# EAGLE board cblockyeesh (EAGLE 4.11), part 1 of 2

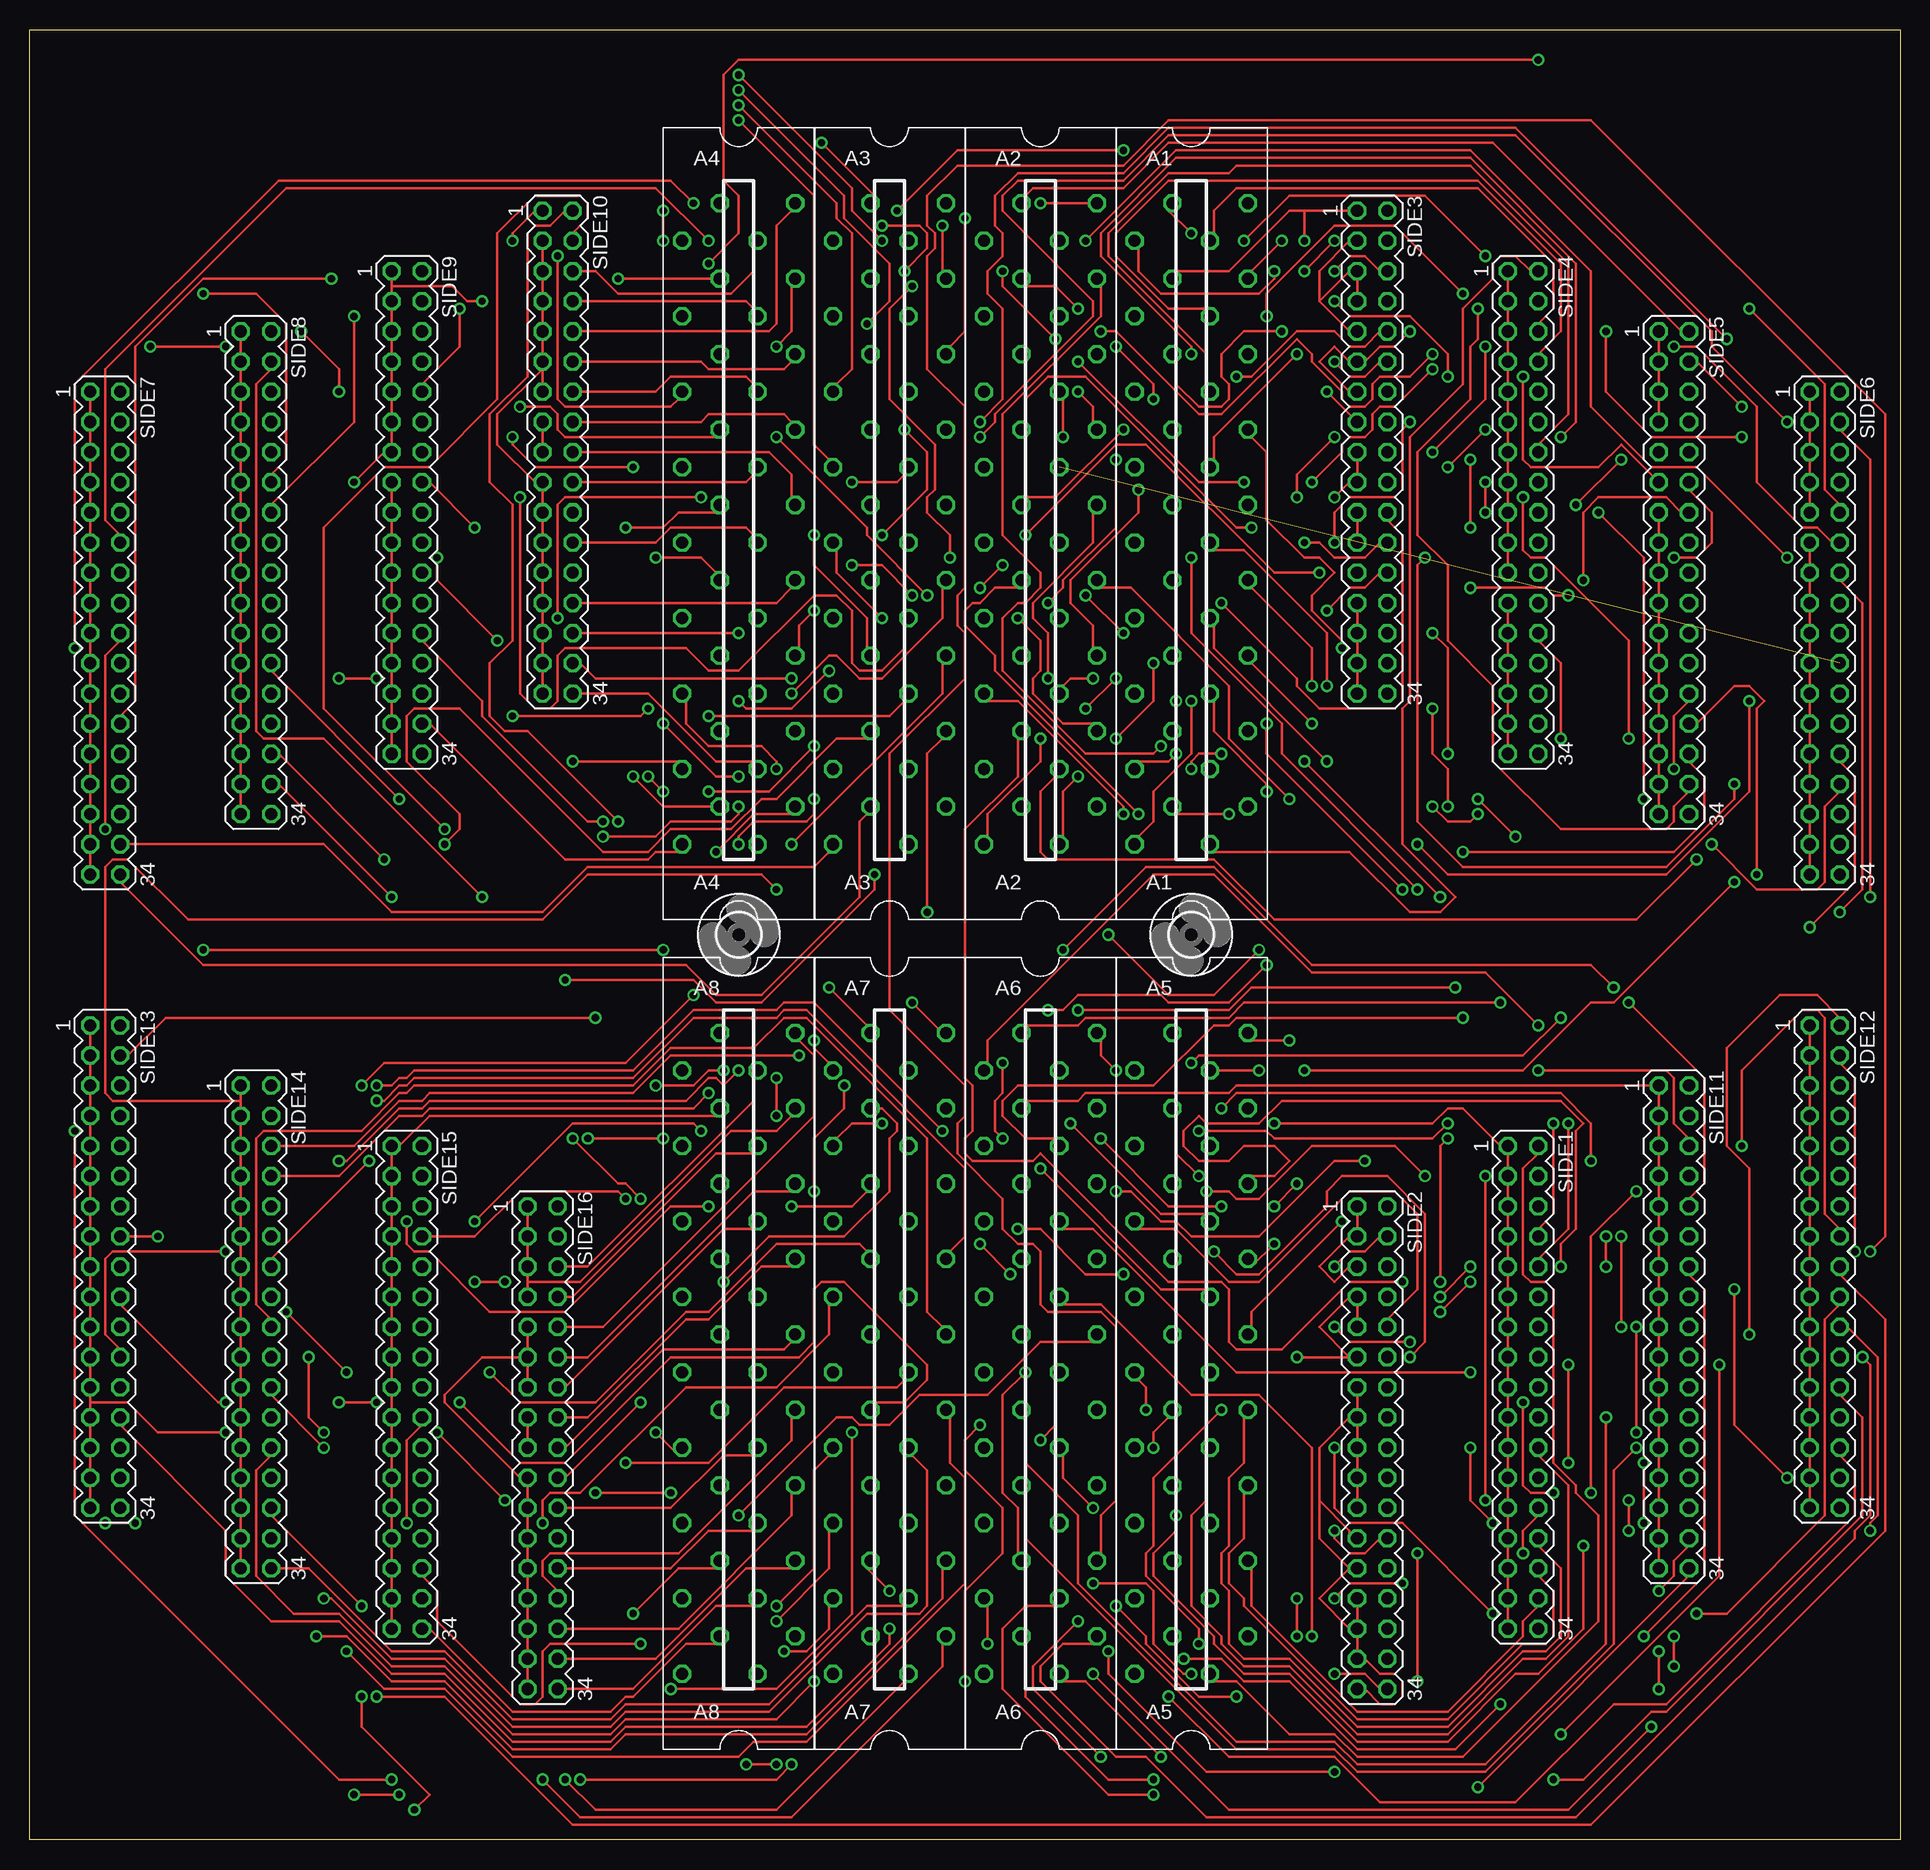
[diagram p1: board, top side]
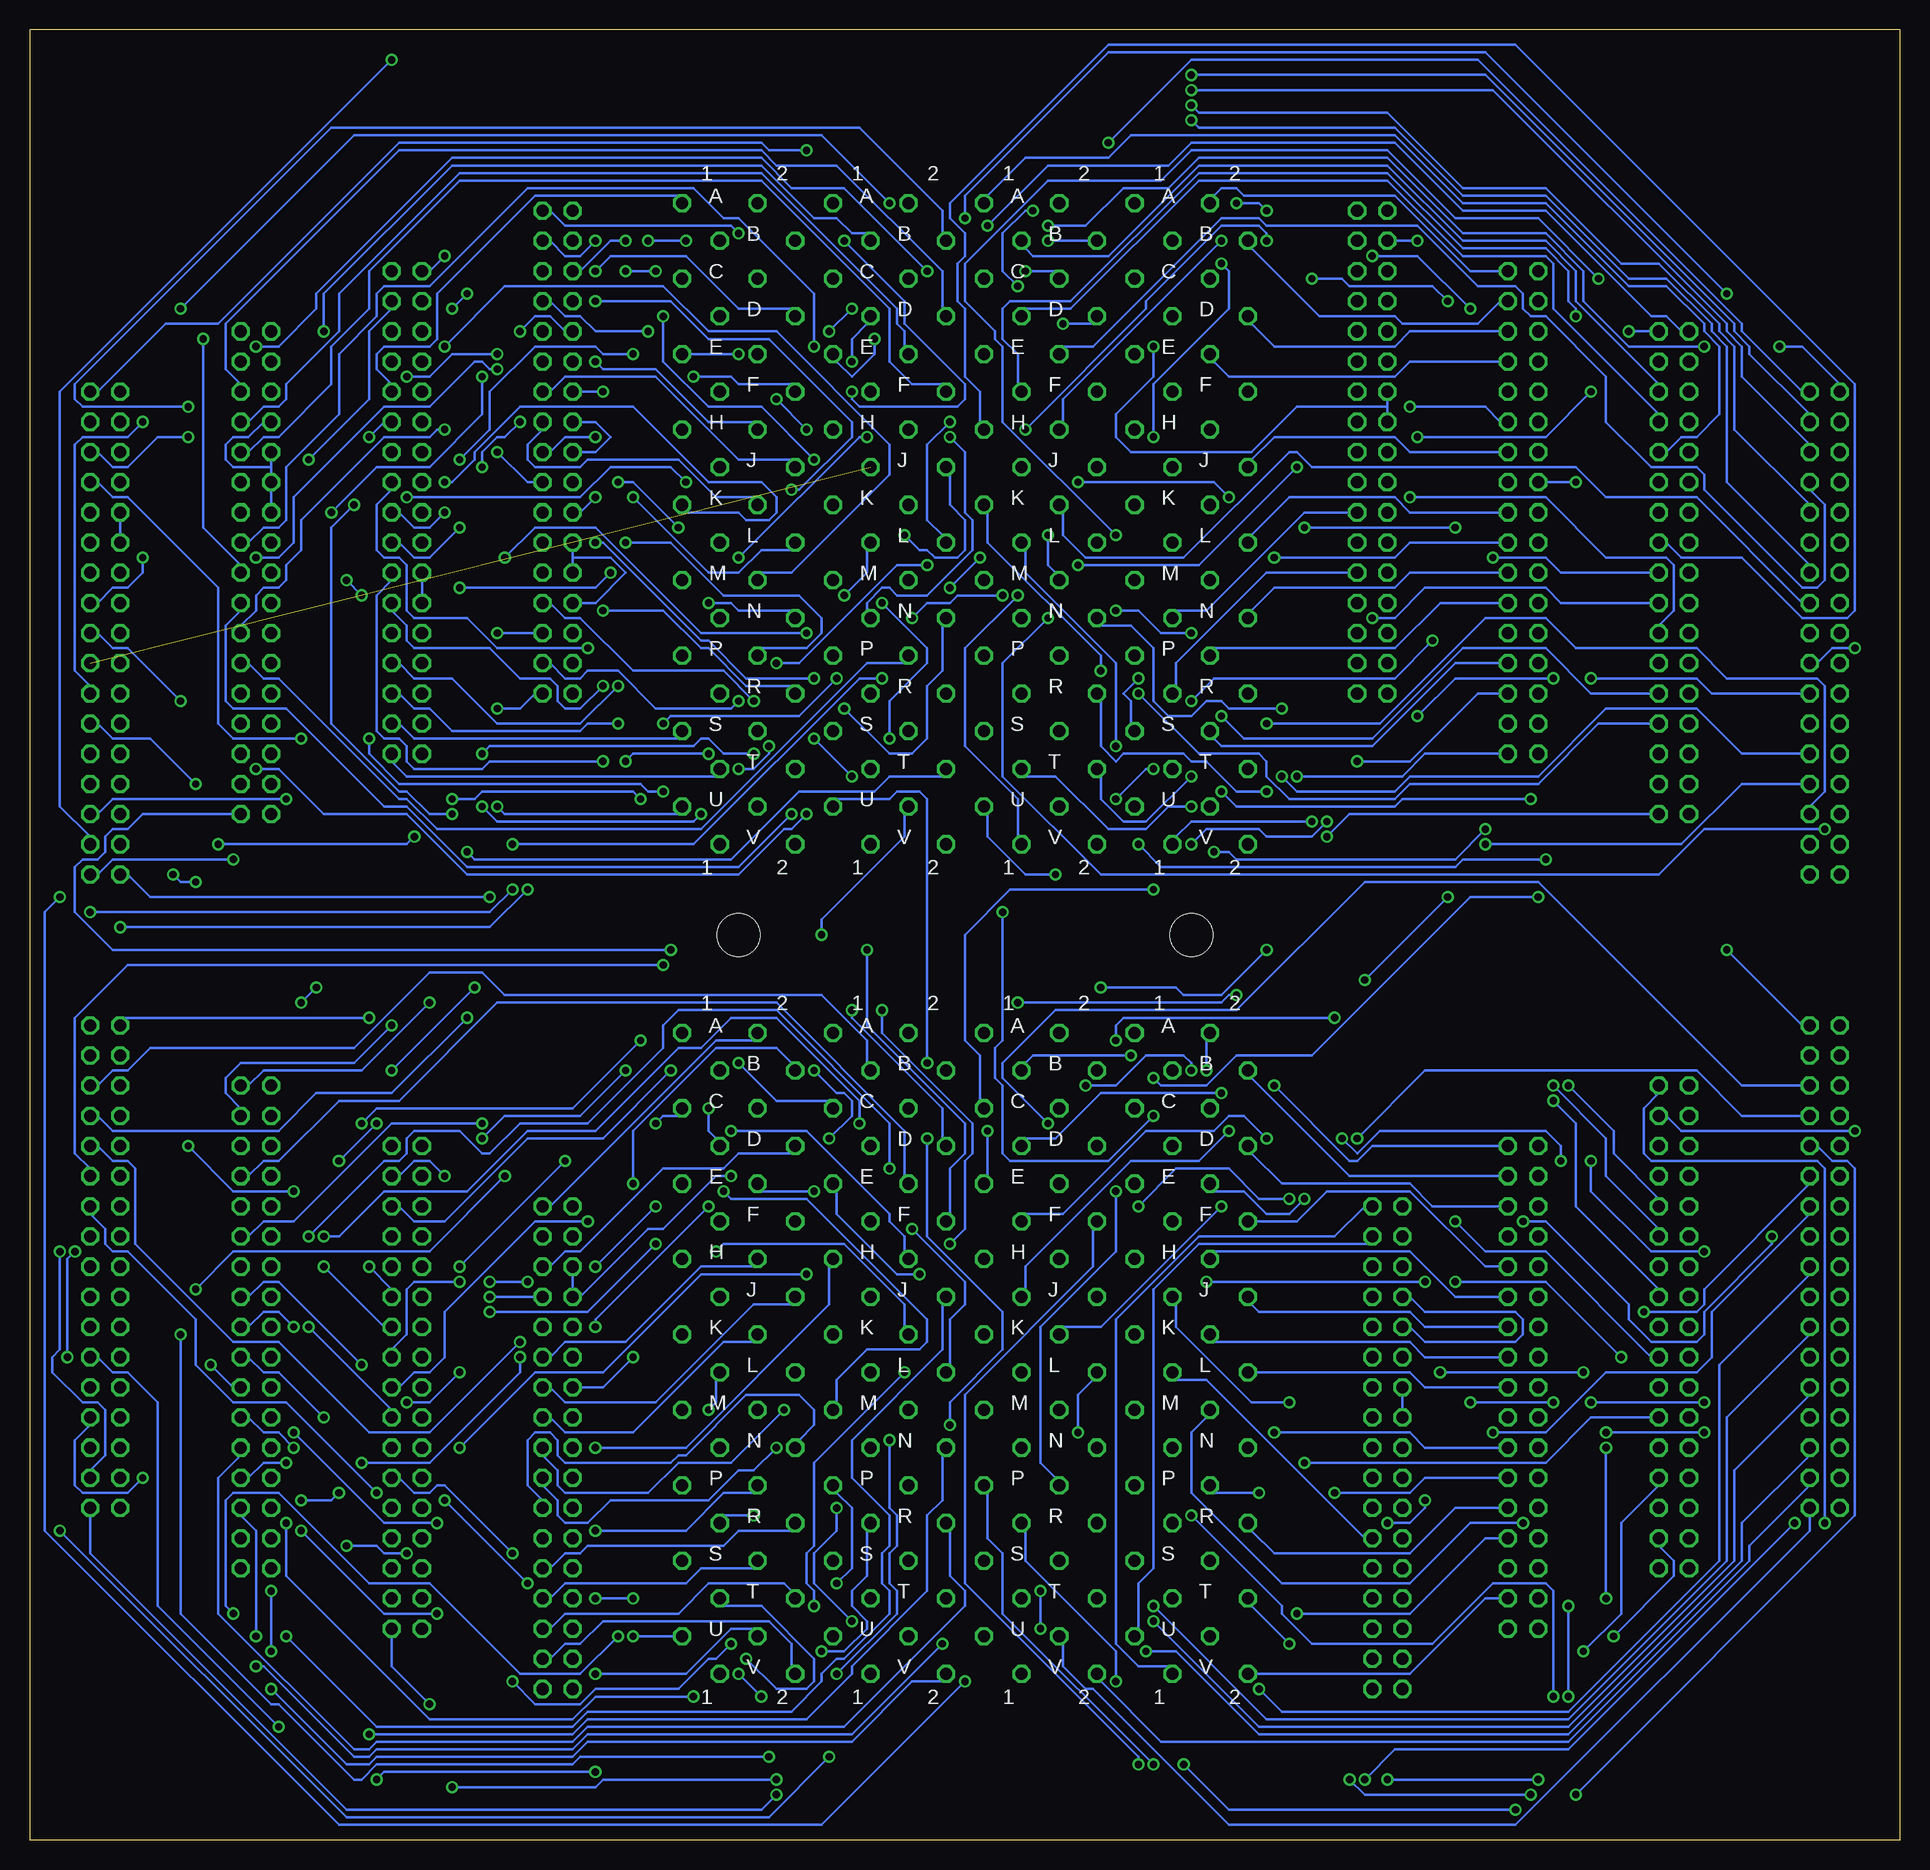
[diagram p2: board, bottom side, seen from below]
Size 157.48 x 152.4 mm. Coordinates in mm from the lower left corner, seen from the top.
Outline: 157.48,0 0,0 0,152.4 157.48,152.4 157.48,0
Copper layers (1*16): Top 0.035mm / dielectric 1.5mm / Bottom 0.035mm
Design rules "olimex8mil": minimum track width 8mil, minimum drill 24mil, track to track 8mil, track to pad 8mil, pad to pad 8mil, via to via 8mil, smd to smd 8mil, copper to edge 40mil, drill to drill 10mil, minimum pad ring 10mil, minimum via ring 8mil, stop-mask expansion 0mil, vias tented up to drill 0mil, thermal gap 10mil
Net classes: 1 Power: width 0.305 mm, drill 0.305 mm

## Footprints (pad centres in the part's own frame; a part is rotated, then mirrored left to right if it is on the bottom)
H807 = drill 1.016 octagon: A1 4.763,28.575; A2 -1.587,28.575; B1 1.587,25.4; B2 -4.763,25.4; C1 4.763,22.225; C2 -1.587,22.225; D1 1.587,19.05; D2 -4.763,19.05; E1 4.763,15.875; E2 -1.587,15.875; F1 1.587,12.7; F2 -4.763,12.7; H1 4.763,9.525; H2 -1.587,9.525; J1 1.587,6.35; J2 -4.763,6.35; K1 4.763,3.175; K2 -1.587,3.175; L1 1.587,0; L2 -4.763,0; M1 4.763,-3.175; M2 -1.587,-3.175; N1 1.587,-6.35; N2 -4.763,-6.35; P1 4.763,-9.525; P2 -1.587,-9.525; R1 1.587,-12.7; R2 -4.763,-12.7; S1 4.763,-15.875; S2 -1.587,-15.875; T1 1.587,-19.05; T2 -4.763,-19.05; U1 4.763,-22.225; U2 -1.587,-22.225; V1 1.587,-25.4; V2 -4.763,-25.4
MA17-2 = drill 1.016 octagon: 1 -20.32,-1.27; 2 -20.32,1.27; 3 -17.78,-1.27; 4 -17.78,1.27; 5 -15.24,-1.27; 6 -15.24,1.27; 7 -12.7,-1.27; 8 -12.7,1.27; 9 -10.16,-1.27; 10 -10.16,1.27; 11 -7.62,-1.27; 12 -7.62,1.27; 13 -5.08,-1.27; 14 -5.08,1.27; 15 -2.54,-1.27; 16 -2.54,1.27; 17 0,-1.27; 18 0,1.27; 19 2.54,-1.27; 20 2.54,1.27; 21 5.08,-1.27; 22 5.08,1.27; 23 7.62,-1.27; 24 7.62,1.27; 25 10.16,-1.27; 26 10.16,1.27; 27 12.7,-1.27; 28 12.7,1.27; 29 15.24,-1.27; 30 15.24,1.27; 31 17.78,-1.27; 32 17.78,1.27; 33 20.32,-1.27; 34 20.32,1.27
3,6 = hole 3.6: 0,0

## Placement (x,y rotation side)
A1  [H807]  97.79,109.22 0 top
A2  [H807]  85.09,109.22 0 top
A3  [H807]  72.39,109.22 0 top
A4  [H807]  59.69,109.22 0 top
A5  [H807]  97.79,39.37 0 top
A6  [H807]  85.09,39.37 0 top
A7  [H807]  72.39,39.37 0 top
A8  [H807]  59.69,39.37 0 top
SIDE1  [MA17-2]  125.73,38.1 270 top
SIDE2  [MA17-2]  113.03,33.02 270 top
SIDE3  [MA17-2]  113.03,116.84 270 top
SIDE4  [MA17-2]  125.73,111.76 270 top
SIDE5  [MA17-2]  138.43,106.68 270 top
SIDE6  [MA17-2]  151.13,101.6 270 top
SIDE7  [MA17-2]  6.35,101.6 270 top
SIDE8  [MA17-2]  19.05,106.68 270 top
SIDE9  [MA17-2]  31.75,111.76 270 top
SIDE10  [MA17-2]  44.45,116.84 270 top
SIDE11  [MA17-2]  138.43,43.18 270 top
SIDE12  [MA17-2]  151.13,48.26 270 top
SIDE13  [MA17-2]  6.35,48.26 270 top
SIDE14  [MA17-2]  19.05,43.18 270 top
SIDE15  [MA17-2]  31.75,38.1 270 top
SIDE16  [MA17-2]  43.18,33.02 270 top
U$5  [3,6]  59.69,76.2 0 top
U$6  [3,6]  97.79,76.2 0 top

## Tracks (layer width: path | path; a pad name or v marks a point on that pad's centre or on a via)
N$1  (via drill 0.61)
  Top 0.203: SIDE2.33 112.39,12.7 113.67,11.43 114.94,11.43 115.57,12.06 115.57,13.34 114.94,13.97 113.67,13.97 112.39,15.24 SIDE2.31 111.76,15.88 111.76,17.14 SIDE2.29 | SIDE2.27 111.76,19.68 111.76,18.41 SIDE2.29 | 111.12,22.86 108.58,20.32 111.12,17.78 SIDE2.29 | 111.12,22.86 SIDE2.25 111.12,22.86 | SIDE2.21 111.76,28.57 111.76,29.84 SIDE2.19 111.76,31.11 111.76,32.38 SIDE2.17 111.76,33.66 111.76,34.92 SIDE2.15 | 108.58,28.57 111.12,26.04 111.12,25.4 SIDE2.23 | 108.58,28.57 108.58,33.02 111.12,35.56 SIDE2.15 | SIDE2.13 111.76,37.47 111.76,36.2 SIDE2.15 | 111.12,22.86 108.58,25.4 108.58,28.57 | SIDE2.1 111.76,52.7 111.76,51.44 SIDE2.3 111.12,50.8 108.58,48.26 109.86,46.99 111.12,48.26 SIDE2.5 | v98.42,55.88 96.52,57.78 96.52,60.96 A5.C2 | 111.12,40.64 108.58,43.18 111.12,45.72 SIDE2.7 111.76,45.09 111.76,43.81 SIDE2.9 | 111.12,40.64 SIDE2.11 111.12,40.64 | v106.68,40.64 111.12,40.64
  Bottom 0.203: v98.42,55.88 99.69,55.88 104.14,51.44 105.41,51.44 111.12,45.72 SIDE2.7 111.76,46.35 111.76,47.62 SIDE2.5 | v106.68,40.64 109.22,38.1 111.12,38.1 SIDE2.13
N$2
  Bottom 0.203: A5.A2 96.52,67.31 99.69,67.31 113.67,53.34 SIDE2.2
N$3  (via drill 0.61)
  Top 0.203: v109.86,48.26 111.12,49.53 112.39,49.53 113.67,50.8 SIDE2.4 | v106.68,55.24 v104.78,53.34
  Bottom 0.203: v104.78,53.34 v109.86,48.26 | v106.68,55.24 106.68,59.69 99.69,66.67 94.61,66.67 93.34,65.41 A5.B2
N$4
  Bottom 0.203: A5.D2 93.34,57.78 97.79,57.78 99.06,56.52 104.14,56.52 111.12,49.53 112.39,49.53 113.67,48.26 SIDE2.6
N$5  (via drill 0.61)
  Top 0.203: v121.28,48.26 v118.75,45.72 | v112.39,57.15 109.86,57.15 103.5,50.8 97.79,50.8 96.52,52.07 95.25,52.07 92.71,54.61 v91.44,54.61
  Bottom 0.203: v118.75,45.72 114.94,45.72 SIDE2.8 | v112.39,57.15 v121.28,48.26 | v91.44,54.61 95.89,54.61 A5.E2
N$6
  Top 0.203: SIDE2.10 114.3,43.81 116.84,46.35 116.84,52.7 114.94,54.61 111.12,54.61 103.5,46.99 100.97,46.99 96.52,51.44 93.34,51.44 A5.F2
N$7
  Bottom 0.203: A5.H2 96.52,48.26 100.97,48.26 107.31,41.91 112.39,41.91 113.67,40.64 SIDE2.12
N$8
  Bottom 0.203: SIDE2.14 113.67,38.1 112.39,36.83 104.78,36.83 96.52,45.09 93.34,45.09 A5.J2
N$9
  Bottom 0.203: SIDE2.16 113.67,35.56 112.39,34.29 106.68,34.29 99.06,41.91 96.52,41.91 A5.K2
N$10  (via drill 0.61)
  Top 0.203: v93.98,36.2 93.98,38.1 93.34,38.73 A5.L2
  Bottom 0.203: v93.98,36.2 98.42,31.75 102.87,31.75 105.41,29.21 112.39,29.21 113.03,29.84 113.03,31.11 114.3,32.38 SIDE2.18
N$11  (via drill 0.61)
  Top 0.203: v94.61,33.02 94.61,34.29 95.89,35.56 A5.M2
  Bottom 0.203: v94.61,33.02 96.52,31.11 97.79,31.11 100.33,28.57 108.58,28.57 110.49,26.67 112.39,26.67 113.03,27.3 113.03,28.57 114.3,29.84 SIDE2.20
N$12
  Bottom 0.203: SIDE2.22 114.3,28.57 115.57,29.84 115.57,33.66 114.94,34.29 113.67,34.29 113.03,33.66 113.03,32.38 112.39,31.75 103.5,31.75 102.87,32.38 102.23,32.38 97.16,37.47 92.71,37.47 91.44,36.2 91.44,34.92 92.71,33.66 A5.N2
N$13  (via drill 0.61)
  Top 0.203: v109.86,26.04 109.86,25.4 111.12,24.13 112.39,24.13 113.67,25.4 SIDE2.24
  Bottom 0.203: v109.86,26.04 102.23,26.04 99.06,29.21 96.52,29.21 A5.P2
N$14
  Bottom 0.203: A5.R2 93.34,26.04 97.79,26.04 99.06,24.77 110.49,24.77 111.12,24.13 112.39,24.13 113.67,22.86 SIDE2.26
N$15
  Bottom 0.203: A5.S2 96.52,22.86 100.97,22.86 102.23,21.59 112.39,21.59 113.67,20.32 SIDE2.28
N$16
  Bottom 0.203: SIDE2.30 113.67,17.78 112.39,19.05 102.87,19.05 100.33,21.59 93.98,21.59 93.34,20.95 A5.T2
N$17  (via drill 0.61)
  Top 0.203: v109.86,13.97 112.39,13.97 113.67,12.7 SIDE2.34
  Bottom 0.203: v109.86,13.97 102.23,13.97 98.42,17.78 96.52,17.78 A5.U2
N$18
  Bottom 0.203: A5.V2 93.34,14.61 93.34,16.51 95.25,18.41 109.22,18.41 111.12,16.51 112.39,16.51 113.67,15.24 SIDE2.32
N$19  (via drill 0.61)
  Top 0.203: v129.54,60.33 129.54,51.44 127,48.9 SIDE1.10 | v106.05,67.31 102.87,67.31 A5.A1
  Bottom 0.203: v129.54,60.33 128.27,61.59 111.76,61.59 v106.05,67.31
N$20  (via drill 0.61)
  Top 0.203: v103.5,64.77 99.69,64.77 A5.B1
  Bottom 0.203: v103.5,64.77 109.22,59.05 115.57,59.05 122.56,52.07 125.09,52.07 126.36,53.34 SIDE1.6
N$21  (via drill 0.61)
  Top 0.203: v128.27,60.33 128.27,52.7 127,51.44 SIDE1.8 | v131.44,57.15 131.44,60.33 128.91,62.87 101.6,62.87 v100.33,61.59
  Bottom 0.203: v131.44,57.15 v128.27,60.33 | v100.33,61.59 100.33,59.69 99.69,59.05 A5.D1
N$22  (via drill 0.61)
  Top 0.203: v128.91,48.26 128.91,50.16 130.18,51.44 130.18,59.69 130.81,60.33 128.91,62.23 105.41,62.23 103.5,60.33 99.06,60.33 98.42,60.96 97.16,59.69 97.16,58.42 98.42,57.15 100.97,57.15 102.23,58.42 104.78,58.42 106.05,57.15 104.78,55.88 102.87,55.88 A5.E1
  Bottom 0.203: v128.91,48.26 127,46.35 SIDE1.12
N$23  (via drill 0.61)
  Top 0.203: v132.72,50.8 v132.72,48.26 | v87.63,60.33 95.25,52.7 99.06,52.7 A5.F1
  Bottom 0.203: v132.72,48.26 127.64,43.18 SIDE1.14 | v132.72,50.8 131.44,50.8 127.64,54.61 120.65,54.61 115.57,59.69 109.86,59.69 102.87,66.67 100.97,66.67 98.42,69.22 94.61,69.22 87.63,62.23 v87.63,60.33
N$24  (via drill 0.61)
  Top 0.203: v118.75,44.45 v121.28,46.99 | v104.78,50.16 102.87,48.26 A5.H1
  Bottom 0.203: v121.28,46.99 125.09,46.99 125.73,46.35 125.73,42.55 127,41.27 SIDE1.16 | v118.75,44.45 110.49,44.45 v104.78,50.16
N$25  (via drill 0.61)
  Top 0.203: v133.99,50.8 v133.99,43.18 | v85.09,56.52 95.25,46.35 99.06,46.35 A5.J1
  Bottom 0.203: v133.99,43.18 127,36.2 SIDE1.20 | v133.99,50.8 127.64,57.15 126.36,57.15 125.73,57.78 125.73,59.05 125.09,59.69 121.28,59.69 119.38,57.78 118.75,57.78 116.2,60.33 110.49,60.33 104.14,66.67 104.14,68.58 102.87,69.85 94.61,69.85 85.09,60.33 v85.09,56.52
N$26  (via drill 0.61)
  Top 0.203: v110.49,52.07 102.87,44.45 102.87,43.18 A5.K1
  Bottom 0.203: v110.49,52.07 114.94,52.07 122.56,44.45 122.56,40.64 123.83,39.37 125.09,39.37 126.36,38.1 SIDE1.18
N$27  (via drill 0.61)
  Top 0.203: v100.33,36.2 94.61,30.48 94.61,24.77 93.98,24.13 93.98,22.23 98.42,17.78 v98.42,16.51 | v116.84,13.34 v116.84,24.13
  Bottom 0.203: v100.33,36.2 99.69,36.83 99.69,38.73 A5.L1 | v98.42,16.51 99.69,15.24 100.33,15.24 102.87,12.7 109.86,12.7 111.12,11.43 114.94,11.43 v116.84,13.34 | v116.84,24.13 122.56,29.84 123.19,29.84 123.83,29.21 125.09,29.21 126.36,30.48 SIDE1.24
N$28
  Top 0.203: A5.M1 102.23,35.56 102.23,31.75 100.97,30.48 100.97,24.77 100.33,24.13 100.33,21.59 100.97,20.95 100.97,16.51 102.23,15.24 106.05,15.24 111.76,9.53 119.38,9.53 125.73,15.88 127.64,15.88 128.91,17.14 128.91,22.86 127,24.77 SIDE1.28
N$29
  Top 0.203: A5.N1 99.06,32.38 99.06,28.57 97.79,27.3 97.79,19.68 100.33,17.14 100.33,16.51 102.23,14.61 106.05,14.61 111.76,8.89 119.38,8.89 125.73,15.24 127.64,15.24 129.54,17.14 129.54,29.84 127,32.38 SIDE1.22
N$30
  Top 0.203: A5.P1 102.23,29.21 102.23,25.4 100.97,24.13 100.97,21.59 102.23,20.32 102.23,19.68 111.76,10.16 119.38,10.16 125.73,16.51 127.64,16.51 128.27,17.14 128.27,20.95 127,22.23 SIDE1.30
N$31  (via drill 0.61)
  Top 0.203: v96.52,27.3 96.52,26.04 94.61,24.13 94.61,22.23 99.69,17.14 99.69,16.51 102.23,13.97 106.05,13.97 111.76,8.26 119.38,8.26 125.09,13.97 127,13.97 130.81,17.78 v130.81,24.77 | v125.73,24.13 125.73,26.04 127,27.3 SIDE1.26
  Bottom 0.203: v96.52,27.3 99.06,27.3 A5.R1 | v130.81,24.77 128.27,24.77 127.64,24.13 v125.73,24.13
N$32
  Top 0.203: A5.S1 102.87,22.86 102.87,19.68 111.76,10.79 119.38,10.79 125.73,17.14 125.73,18.41 127,19.68 SIDE1.32
N$33  (via drill 0.61)
  Top 0.203: v123.83,11.43 120.02,7.62 111.76,7.62 106.05,13.34 102.23,13.34 100.33,15.24 v97.16,15.24
  Bottom 0.203: v123.83,11.43 127,14.61 127,17.14 SIDE1.34 | v97.16,15.24 94.61,12.7 92.08,12.7 91.44,13.34 91.44,15.24 95.89,19.68 99.06,19.68 A5.T1
N$34  (via drill 0.61)
  Top 0.203: v106.68,17.14 v106.68,20.32 | v109.86,20.32 111.12,21.59 v115.57,21.59 | v122.56,28.57 v122.56,55.88
  Bottom 0.203: v106.68,17.14 102.87,17.14 A5.U1 | v106.68,20.32 v109.86,20.32 | v115.57,21.59 v122.56,28.57 | v122.56,55.88 123.83,57.15 125.09,57.15 126.36,55.88 SIDE1.4
N$35
  Top 0.203: A5.V1 99.69,13.34 101.6,13.34 106.05,8.89 109.86,8.89 111.76,6.99 120.65,6.99 132.08,18.41 132.08,27.3 130.18,29.21 130.18,29.84 128.27,31.75 128.27,46.35 127.64,46.99 126.36,46.99 125.73,47.62 125.73,56.52 127,57.78 SIDE1.2
N$36  (via drill 0.61)
  Top 0.203: SIDE1.33 124.46,18.41 124.46,19.68 SIDE1.31 124.46,20.95 124.46,22.23 SIDE1.29 124.46,23.5 124.46,24.77 SIDE1.27 124.46,26.04 124.46,27.3 SIDE1.25 124.46,28.57 124.46,29.84 SIDE1.23 124.46,31.11 124.46,32.38 SIDE1.21 124.46,33.66 124.46,34.92 SIDE1.19 124.46,36.2 124.46,37.47 SIDE1.17 124.46,38.73 124.46,40.01 SIDE1.15 124.46,41.27 124.46,42.55 SIDE1.13 124.46,43.81 124.46,45.09 SIDE1.11 124.46,46.35 124.46,47.62 SIDE1.9 124.46,48.9 124.46,50.16 SIDE1.7 124.46,51.44 124.46,52.7 SIDE1.5 124.46,53.98 124.46,55.24 SIDE1.3 124.46,56.52 124.46,57.78 SIDE1.1 123.83,58.42 120.65,61.59 119.38,61.59 118.11,60.33 v104.78,60.33
  Bottom 0.203: v104.78,60.33 104.14,60.96 102.87,60.96 A5.C1
N$37  (via drill 0.61)
  Top 0.203: 108.58,129.54 111.12,127 SIDE3.9 | 108.58,129.54 111.12,132.08 SIDE3.5 111.76,131.44 111.76,130.18 SIDE3.7 | 108.58,129.54 108.58,132.08 111.12,134.62 SIDE3.3 | 107.31,137.16 111.12,137.16 SIDE3.1 | 107.31,137.16 106.05,137.16 100.97,132.08 96.52,132.08 A1.C2 | v107.31,134.62 107.31,137.16 | SIDE3.33 111.76,97.16 111.76,98.42 SIDE3.31 111.76,99.69 111.76,100.97 SIDE3.29 111.76,102.23 111.76,103.5 SIDE3.27 | SIDE3.21 111.76,111.12 111.76,109.86 SIDE3.23 | SIDE3.13 111.12,121.92 108.58,124.46 109.86,125.73 111.12,124.46 SIDE3.11 112.39,124.46 113.67,125.73 114.94,125.73 v116.2,127 | SIDE3.17 111.76,116.2 111.76,114.94 SIDE3.19 111.12,114.3 v109.86,113.03 | SIDE3.15 v109.22,121.92
  Bottom 0.203: v107.31,134.62 108.58,134.62 111.12,132.08 SIDE3.5 | 111.76,107.95 111.76,108.58 SIDE3.23 | 111.76,107.95 111.76,107.31 SIDE3.25 | SIDE3.15 111.12,119.38 109.86,119.38 108.58,118.11 109.86,116.84 111.12,116.84 SIDE3.17 | v109.22,121.92 111.12,121.92 SIDE3.13 | v109.86,113.03 111.12,111.76 SIDE3.21 | 111.76,107.95 108.58,107.95 107.31,106.68 109.86,104.14 111.12,104.14 SIDE3.27 | v116.2,127 114.94,128.27 113.67,128.27 112.39,127 SIDE3.9
N$38  (via drill 0.61)
  Top 0.203: v97.79,135.25 95.89,137.16 A1.A2
  Bottom 0.203: v97.79,135.25 98.42,135.89 112.39,135.89 113.67,137.16 SIDE3.2
N$39  (via drill 0.61)
  Top 0.203: v104.78,132.08 104.78,131.44 103.5,130.18 95.25,130.18 93.34,132.08 93.34,133.99 A1.B2 | v107.31,132.08 v109.86,134.62
  Bottom 0.203: v104.78,132.08 v107.31,132.08 | v109.86,134.62 111.12,133.35 112.39,133.35 113.67,134.62 SIDE3.4
N$40  (via drill 0.61)
  Top 0.203: v109.86,132.08 111.12,133.35 112.39,133.35 113.67,132.08 SIDE3.6
  Bottom 0.203: v109.86,132.08 108.58,133.35 102.23,133.35 97.79,128.91 93.34,128.91 A1.D2
N$41  (via drill 0.61)
  Top 0.203: v105.41,127 102.23,127 100.33,125.09 100.33,123.19 100.97,122.56 100.97,121.28 100.33,120.65 98.42,120.65 96.52,122.56 96.52,124.46 A1.E2
  Bottom 0.203: v105.41,127 109.86,127 111.12,128.27 112.39,128.27 113.67,129.54 SIDE3.8
N$42  (via drill 0.61)
  Top 0.203: v101.6,123.19 102.87,123.19 106.68,127 109.86,127 111.12,125.73 112.39,125.73 113.67,127 SIDE3.10
  Bottom 0.203: v101.6,123.19 98.42,123.19 97.79,122.56 93.34,122.56 A1.F2
N$43  (via drill 0.61)
  Top 0.203: v109.86,124.46 111.12,123.19 112.39,123.19 113.67,124.46 SIDE3.12
  Bottom 0.203: v109.86,124.46 109.22,123.83 104.78,123.83 100.33,119.38 96.52,119.38 A1.H2
N$44
  Bottom 0.203: A1.J2 93.34,116.2 97.79,116.2 104.78,123.19 112.39,123.19 113.67,121.92 SIDE3.14
N$45
  Bottom 0.203: A1.K2 96.52,113.03 99.69,113.03 102.87,116.2 110.49,116.2 111.12,115.57 114.94,115.57 115.57,116.2 115.57,117.47 114.3,118.75 SIDE3.16
N$46  (via drill 0.61)
  Top 0.203: v106.68,113.03 106.68,114.94 v109.86,118.11
  Bottom 0.203: v106.68,113.03 100.33,106.68 97.79,106.68 95.89,108.58 93.34,108.58 A1.L2 | v109.86,118.11 112.39,118.11 113.67,116.84 SIDE3.18
N$47  (via drill 0.61)
  Top 0.203: v122.56,125.73 122.56,121.28 v118.11,116.84
  Bottom 0.203: v122.56,125.73 117.47,130.81 104.14,130.81 100.33,127 94.61,127 85.09,117.47 85.09,114.94 93.34,106.68 95.89,106.68 A1.M2 | v118.11,116.84 115.57,114.3 114.94,114.3 SIDE3.20
N$48  (via drill 0.61)
  Top 0.203: v100.33,104.14 106.68,97.79 106.68,97.16 108.58,95.25 114.94,95.25 115.57,95.89 115.57,109.86 114.3,111.12 SIDE3.22
  Bottom 0.203: v100.33,104.14 98.42,104.14 97.79,103.5 93.34,103.5 A1.N2
N$49  (via drill 0.61)
  Top 0.203: v107.31,109.22 108.58,109.22 109.86,107.95 112.39,107.95 113.67,109.22 SIDE3.24
  Bottom 0.203: v107.31,109.22 103.5,109.22 99.06,104.78 92.71,104.78 90.81,102.87 90.81,101.6 92.08,100.33 95.89,100.33 A1.P2
N$50  (via drill 0.61)
  Top 0.203: v109.22,103.5 111.12,105.41 112.39,105.41 113.67,106.68 SIDE3.26
  Bottom 0.203: v109.22,103.5 104.14,103.5 100.97,100.33 100.33,100.33 97.16,97.16 93.34,97.16 A1.R2
N$51  (via drill 0.61)
  Top 0.203: v96.52,95.89 96.52,93.98 A1.S2
  Bottom 0.203: v96.52,95.89 99.06,98.42 106.68,98.42 111.12,102.87 112.39,102.87 113.67,104.14 SIDE3.28
N$52  (via drill 0.61)
  Top 0.203: v96.52,91.44 95.89,90.81 93.34,90.81 A1.T2 | v119.38,91.44 119.38,100.33 v118.11,101.6
  Bottom 0.203: v96.52,91.44 99.06,91.44 100.33,92.71 100.97,92.71 101.6,92.08 118.75,92.08 v119.38,91.44 | v118.11,101.6 114.94,101.6 SIDE3.30
N$53  (via drill 0.61)
  Top 0.203: v100.97,86.36 96.52,86.36 A1.U2 | v119.38,87 119.38,90.17 118.11,91.44 v118.11,95.25
  Bottom 0.203: v100.97,86.36 101.6,85.72 118.11,85.72 v119.38,87 | v118.11,95.25 116.2,95.25 114.94,96.52 SIDE3.34
N$54  (via drill 0.61)
  Top 0.203: v97.79,95.89 97.79,91.44 94.61,88.27 94.61,85.72 93.34,84.45 A1.V2
  Bottom 0.203: v97.79,95.89 98.42,95.25 104.78,95.25 107.95,98.42 110.49,98.42 111.12,97.79 112.39,97.79 113.67,99.06 SIDE3.32
N$55
  Bottom 0.203: A1.A1 102.87,138.43 114.94,138.43 123.19,130.18 123.19,126.36 123.83,125.73 127.64,125.73 128.27,125.09 128.27,123.83 127,122.56 SIDE4.10
N$56
  Top 0.203: A1.B1 99.69,135.25 99.69,137.16 101.6,139.06 121.92,139.06 128.27,132.72 128.27,128.91 127,127.64 SIDE4.6
N$57
  Top 0.203: SIDE4.8 127,125.09 128.91,127 128.91,132.72 121.92,139.7 95.89,139.7 91.44,135.25 91.44,133.35 95.89,128.91 99.06,128.91 A1.D1
N$58  (via drill 0.61)
  Top 0.203: v128.91,118.11 130.18,119.38 130.18,132.72 121.28,141.6 96.52,141.6 90.17,135.25 90.17,133.35 97.79,125.73 v97.79,125.09
  Bottom 0.203: v128.91,118.11 127.64,119.38 SIDE4.12 | v97.79,125.09 102.23,125.09 A1.E1
N$59
  Top 0.203: A1.F1 99.06,122.56 99.06,125.09 90.81,133.35 90.81,135.25 95.89,140.34 100.97,140.34 101.6,140.97 121.28,140.97 129.54,132.72 129.54,120.02 127,117.47 SIDE4.14
N$60  (via drill 0.61)
  Top 0.203: v110.49,100.33 110.49,100.97 107.95,103.5 107.95,104.78 109.86,106.68 108.58,107.95 107.31,107.95 104.14,111.12 104.14,116.84 102.87,118.11 A1.H1
  Bottom 0.203: v110.49,100.33 118.11,100.33 120.65,102.87 125.09,102.87 125.73,103.5 125.73,107.31 126.36,107.95 127.64,107.95 128.27,108.58 128.27,112.39 127,113.67 SIDE4.16
N$61  (via drill 0.61)
  Top 0.203: v106.68,125.09 99.69,118.11 99.69,116.2 A1.J1 | v121.28,116.2 v121.28,110.49
  Bottom 0.203: v106.68,125.09 109.22,125.09 109.86,125.73 114.94,125.73 118.75,121.92 118.75,118.75 v121.28,116.2 | v121.28,110.49 123.83,107.95 125.09,107.95 126.36,109.22 SIDE4.20
N$62  (via drill 0.61)
  Top 0.203: v122.56,114.3 v122.56,111.76
  Bottom 0.203: v122.56,114.3 121.92,114.3 120.02,116.2 120.02,116.84 116.2,120.65 106.68,120.65 100.33,114.3 95.89,114.3 94.61,113.03 94.61,111.76 95.25,111.12 97.16,111.12 97.79,111.76 102.23,111.76 A1.K1 | v122.56,111.76 123.83,110.49 125.09,110.49 126.36,111.76 SIDE4.18
N$63  (via drill 0.61)
  Top 0.203: v109.22,97.16 109.22,101.6 102.23,108.58 99.69,108.58 A1.L1
  Bottom 0.203: v109.22,97.16 111.12,95.25 112.39,95.25 113.03,95.89 113.03,97.16 113.67,97.79 116.2,97.79 118.75,100.33 125.09,100.33 125.73,100.97 125.73,102.23 127,103.5 SIDE4.24
N$64  (via drill 0.61)
  Top 0.203: v107.95,97.16 107.95,100.33 102.87,105.41 A1.M1
  Bottom 0.203: v107.95,97.16 111.12,93.98 118.11,93.98 121.92,97.79 125.09,97.79 126.36,99.06 SIDE4.28
N$65  (via drill 0.61)
  Top 0.203: v109.22,90.81 99.69,100.33 99.69,102.23 A1.N1
  Bottom 0.203: v109.22,90.81 118.75,90.81 119.38,90.17 125.09,90.17 125.73,90.81 125.73,92.08 126.36,92.71 127.64,92.71 128.27,93.34 128.27,104.78 127,106.05 SIDE4.22
N$66  (via drill 0.61)
  Top 0.203: v107.95,93.98 102.87,99.06 A1.P1
  Bottom 0.203: v107.95,93.98 110.49,93.98 111.12,93.34 121.92,93.34 123.83,95.25 125.09,95.25 126.36,96.52 SIDE4.30
N$67  (via drill 0.61)
  Top 0.203: v104.14,88.27 104.14,88.9 99.69,93.34 99.69,95.89 A1.R1 | v128.91,92.71 128.91,99.06 127,100.97 SIDE4.26
  Bottom 0.203: v104.14,88.27 105.41,88.27 106.05,88.9 126.36,88.9 128.91,91.44 v128.91,92.71
N$68
  Bottom 0.203: A1.S1 102.87,92.71 125.09,92.71 126.36,93.98 SIDE4.32
N$69
  Bottom 0.203: A1.T1 99.69,89.53 125.73,89.53 127,90.81 SIDE4.34
N$70  (via drill 0.61)
  Top 0.203: v118.11,87 119.38,85.72 121.28,85.72 v121.92,86.36 | v133.99,116.2 v130.18,112.39
  Bottom 0.203: v118.11,87 117.47,86.36 102.87,86.36 A1.U1 | v121.92,86.36 123.83,86.36 125.73,88.27 126.36,88.27 132.08,93.98 132.08,110.49 v130.18,112.39 | v133.99,116.2 128.91,121.28 128.91,127 127,128.91 SIDE4.4
N$71
  Top 0.203: A1.V1 99.69,83.19 111.12,83.19 116.2,78.11 118.75,78.11 120.02,79.38 115.57,83.82 115.57,95.25 116.2,95.89 116.2,118.11 120.65,122.56 120.65,128.91 123.19,131.44 123.19,132.72 123.83,133.35 125.09,133.35 126.36,132.08 SIDE4.2
N$72  (via drill 0.61)
  Top 0.203: v105.41,134.62 102.87,132.08 A1.C1 | v102.23,134.62 106.05,138.43 117.47,138.43 v122.56,133.35 | SIDE4.33 124.46,92.08 124.46,93.34 SIDE4.31 124.46,94.61 124.46,95.89 SIDE4.29 124.46,97.16 124.46,98.42 SIDE4.27 124.46,99.69 124.46,100.97 SIDE4.25 124.46,102.23 124.46,103.5 SIDE4.23 | SIDE4.21 124.46,107.31 124.46,108.58 SIDE4.19 124.46,109.86 124.46,111.12 SIDE4.17 124.46,112.39 124.46,113.67 SIDE4.15 124.46,114.94 124.46,116.2 SIDE4.13 124.46,117.47 124.46,118.75 SIDE4.11 124.46,120.02 124.46,121.28 SIDE4.9 124.46,122.56 124.46,123.83 SIDE4.7 124.46,125.09 124.46,126.36 SIDE4.5 124.46,127.64 124.46,128.91 SIDE4.3 124.46,130.18 124.46,131.44 SIDE4.1
  Bottom 0.203: v102.23,134.62 v105.41,134.62 | v122.56,133.35 123.83,132.08 SIDE4.1 | SIDE4.21 124.46,106.05 124.46,104.78 SIDE4.23
N$73  (via drill 0.61)
  Top 0.203: SIDE5.33 137.16,87 137.16,88.27 SIDE5.31 137.16,89.53 137.16,90.81 SIDE5.29 137.16,92.08 137.16,93.34 SIDE5.27 137.16,94.61 137.16,95.89 SIDE5.25 137.16,97.16 137.16,98.42 SIDE5.23 137.16,99.69 137.16,100.97 SIDE5.21 137.16,102.23 137.16,103.5 SIDE5.19 137.16,104.78 137.16,106.05 SIDE5.17 137.16,107.31 137.16,108.58 SIDE5.15 137.16,109.86 137.16,111.12 SIDE5.13 | SIDE5.7 137.16,120.02 137.16,121.28 SIDE5.5 137.16,122.56 137.16,123.83 SIDE5.3 137.16,125.09 137.16,126.36 SIDE5.1 | v88.27,128.91 86.36,130.81 83.82,130.81 A2.C2 | v90.17,127 91.44,127 98.42,120.02 100.33,120.02 106.68,126.36 107.95,125.09 107.95,124.46 110.49,121.92 110.49,121.28 111.12,120.65 112.39,120.65 113.03,121.28 113.03,122.56 113.67,123.19 116.2,123.19 v118.11,125.09 | v125.73,123.19 125.73,116.2 126.36,115.57 132.08,115.57 133.99,117.47 SIDE5.11
  Bottom 0.203: v90.17,127 v88.27,128.91 | v118.11,125.09 121.92,125.09 123.83,123.19 v125.73,123.19 | 137.16,115.57 137.16,114.94 SIDE5.11 137.16,113.67 137.16,112.39 SIDE5.13 | 137.16,115.57 137.16,116.2 SIDE5.9 | 137.16,115.57 140.34,115.57 140.97,116.2 140.97,117.47 140.34,118.11 139.06,118.11 137.79,119.38 SIDE5.7
N$74
  Top 0.203: SIDE5.2 139.06,127 123.19,142.88 95.89,142.88 92.08,139.06 84.45,139.06 83.82,138.43 A2.A2
N$75  (via drill 0.61)
  Top 0.203: v144.15,120.65 140.34,124.46 SIDE5.4
  Bottom 0.203: v144.15,120.65 153.03,120.65 153.67,121.28 153.67,122.56 132.08,144.15 87.63,144.15 80.64,137.16 80.64,135.25 A2.B2
N$76
  Bottom 0.203: A2.D2 80.64,128.91 80.64,132.08 89.53,140.97 94.61,140.97 95.89,142.24 126.36,142.24 140.97,127.64 140.97,123.83 139.7,122.56 SIDE5.6
N$77
  Bottom 0.203: A2.E2 83.82,125.73 83.82,127 84.45,127.64 84.45,128.91 95.89,140.34 121.28,140.34 131.44,130.18 131.44,127 135.89,122.56 135.89,121.28 136.53,120.65 137.79,120.65 139.06,119.38 SIDE5.8
N$78
  Bottom 0.203: SIDE5.10 139.06,116.84 137.79,118.11 136.53,118.11 132.08,122.56 132.08,125.73 128.91,128.91 128.91,132.08 121.28,139.7 95.89,139.7 85.09,128.91 85.09,124.46 83.19,122.56 80.64,122.56 A2.F2
N$79  (via drill 0.61)
  Top 0.203: v102.87,110.49 101.6,110.49 88.9,123.19 85.72,123.19 83.82,121.28 83.82,119.38 A2.H2 | v107.95,114.3 110.49,116.84 110.49,117.47 111.12,118.11 112.39,118.11 113.03,118.75 113.03,120.02 113.67,120.65 114.94,120.65 v118.11,123.83 | v138.43,107.95 140.34,107.95 141.6,109.22 141.6,111.76 139.7,113.67 SIDE5.12
  Bottom 0.203: v102.87,110.49 106.68,114.3 v107.95,114.3 | v118.11,123.83 118.75,123.83 119.38,124.46 120.02,124.46 123.83,120.65 127.64,120.65 135.25,113.03 135.25,109.22 136.53,107.95 v138.43,107.95
N$80  (via drill 0.61)
  Top 0.203: v130.81,106.05 130.81,111.76 132.08,113.03 137.79,113.03 139.06,111.76 SIDE5.14 | v129.54,104.78 128.27,104.78 127.64,105.41 v121.28,105.41 | v108.58,106.68 104.78,106.68 93.98,117.47 91.44,117.47 v83.82,109.86
  Bottom 0.203: v129.54,104.78 v130.81,106.05 | v121.28,105.41 109.86,105.41 v108.58,106.68 | v83.82,109.86 82.55,108.58 81.92,108.58 81.28,107.95 79.38,107.95 78.74,108.58 78.74,111.12 80.01,112.39 80.01,114.94 A2.J2
N$81  (via drill 0.61)
  Top 0.203: v92.08,118.75 86.36,113.03 83.82,113.03 A2.K2 | v94.61,121.28 94.61,122.56 v91.44,125.73
  Bottom 0.203: v94.61,121.28 v92.08,118.75 | v91.44,125.73 91.44,130.18 97.79,136.53 99.06,136.53 101.6,139.06 115.57,139.06 123.83,130.81 127.64,130.81 128.27,130.18 128.27,128.27 131.44,125.09 131.44,120.02 135.89,115.57 135.89,111.12 136.53,110.49 137.79,110.49 139.06,109.22 SIDE5.16
N$82  (via drill 0.61)
  Top 0.203: v142.88,126.36 125.09,144.15 95.89,144.15 92.08,140.34 83.19,140.34 81.28,138.43 81.28,135.89 81.92,135.25 81.92,133.35 80.64,132.08 80.64,130.18 81.92,128.91 81.92,121.28 v80.01,119.38
  Bottom 0.203: v142.88,126.36 142.88,110.49 139.7,107.31 SIDE5.18 | v80.01,119.38 81.92,117.47 81.92,111.12 80.64,109.86 A2.L2
N$83  (via drill 0.61)
  Top 0.203: v93.34,86.36 81.28,98.42 81.28,99.69 78.74,102.23 78.74,103.5 79.38,104.14 80.01,104.14 81.28,105.41 83.19,105.41 A2.M2
  Bottom 0.203: v93.34,86.36 97.79,81.92 120.65,81.92 125.73,87 127.64,87 135.89,95.25 140.34,95.25 140.97,95.89 140.97,102.23 139.7,103.5 SIDE5.20
N$84  (via drill 0.61)
  Top 0.203: v88.9,95.25 v91.44,97.79 | v109.86,109.22 109.86,111.76 111.12,113.03 114.94,113.03 115.57,113.67 115.57,118.75 v116.2,119.38 | v119.38,115.57 v122.56,118.75
  Bottom 0.203: v88.9,95.25 85.09,91.44 83.19,91.44 81.92,92.71 81.92,97.16 80.64,98.42 80.64,102.23 A2.N2 | v91.44,97.79 97.16,97.79 100.33,100.97 100.97,100.97 109.22,109.22 v109.86,109.22 | v116.2,119.38 117.47,118.11 118.11,118.11 119.38,116.84 v119.38,115.57 | v122.56,118.75 123.19,118.75 123.83,118.11 127.64,118.11 134.62,111.12 134.62,108.58 135.89,107.31 135.89,106.05 136.53,105.41 137.79,105.41 138.43,104.78 138.43,103.5 139.7,102.23 SIDE5.22
N$85
  Bottom 0.203: A2.P2 83.82,99.06 87,99.06 100.97,85.09 123.19,85.09 125.73,87.63 126.36,87.63 136.53,97.79 137.79,97.79 139.06,99.06 SIDE5.24
N$86  (via drill 0.61)
  Top 0.203: v92.08,86.36 92.08,87 83.19,95.89 80.64,95.89 A2.R2 | v138.43,90.17 138.43,94.61 139.7,95.89 SIDE5.26
  Bottom 0.203: v92.08,86.36 93.34,85.09 93.98,85.09 97.79,81.28 120.65,81.28 125.73,86.36 132.72,86.36 136.53,90.17 v138.43,90.17
N$87  (via drill 0.61)
  Top 0.203: v115.57,46.99 111.12,46.99 105.41,41.27 101.6,41.27 100.97,41.91 100.97,46.35 100.33,46.99 95.89,46.99 85.09,57.78 84.45,57.15 79.38,57.15 78.74,57.78 78.74,59.05 79.38,59.69 79.38,63.5 78.74,64.14 78.74,85.09 83.19,89.53 83.19,92.71 A2.S2 | v118.75,46.99 118.75,58.42 v119.38,59.05 | v107.31,64.77 125.73,64.77 131.44,70.48 133.35,70.48 v143.51,80.64 | v145.41,81.28 145.41,95.25 146.05,95.89 144.78,97.16 143.51,97.16 140.34,93.98 SIDE5.28
  Bottom 0.203: v115.57,46.99 v118.75,46.99 | v119.38,59.05 117.47,60.96 111.12,60.96 v107.31,64.77 | v143.51,80.64 144.78,80.64 v145.41,81.28
N$88  (via drill 0.61)
  Top 0.203: v120.65,83.19 138.43,83.19 140.97,85.72 140.97,89.53 139.7,90.81 SIDE5.30
  Bottom 0.203: v120.65,83.19 120.02,82.55 98.42,82.55 92.71,88.27 86.36,88.27 85.09,89.53 80.64,89.53 A2.T2
N$89  (via drill 0.61)
  Top 0.203: v103.5,74.93 99.69,71.12 95.89,71.12 v90.81,76.2
  Bottom 0.203: v103.5,74.93 150.5,74.93 153.67,78.11 153.67,81.92 153.03,82.55 151.76,82.55 151.13,83.19 151.13,84.45 150.5,85.09 149.22,85.09 147.96,86.36 140.34,86.36 SIDE5.34 | v90.81,76.2 90.81,77.47 83.82,84.45 83.82,86.36 A2.U2
N$90  (via drill 0.61)
  Top 0.203: v85.09,92.71 85.09,90.81 80.64,86.36 80.64,84.45 A2.V2 | v85.72,104.14 87,105.41 87,106.05 91.44,110.49 v91.44,116.2 | v104.14,128.27 104.14,130.18 109.86,135.89 114.94,135.89 v120.65,130.18 | v121.92,128.91 121.92,126.36 121.28,125.73 121.28,121.28 116.84,116.84 116.84,109.86 119.38,107.31 119.38,100.97 123.19,97.16 123.19,90.81 128.91,85.09 137.79,85.09 138.43,85.72 138.43,87 139.7,88.27 SIDE5.32
  Bottom 0.203: v85.09,92.71 85.09,95.89 81.92,99.06 81.92,100.33 v85.72,104.14 | v91.44,116.2 95.89,120.65 100.33,120.65 104.14,124.46 v104.14,128.27 | v120.65,130.18 v121.92,128.91
N$91  (via drill 0.61)
  Top 0.203: v85.09,137.79 89.53,137.79 A2.A1 | v144.78,128.91 151.13,122.56 151.13,113.67 152.4,112.39 SIDE6.10
  Bottom 0.203: v85.09,137.79 90.81,143.51 130.18,143.51 v144.78,128.91
N$92  (via drill 0.61)
  Top 0.203: v132.72,127 132.72,121.92 136.53,118.11 v144.15,118.11
  Bottom 0.203: v132.72,127 132.72,130.18 121.92,140.97 95.89,140.97 91.44,136.53 89.53,136.53 88.27,135.25 87,135.25 A2.B1 | v144.15,118.11 146.69,118.11 149.22,115.57 150.5,115.57 151.76,116.84 SIDE6.6
N$93  (via drill 0.61)
  Top 0.203: v134.62,92.71 134.62,100.97 127.64,107.95 126.36,107.95 125.73,108.58 v125.73,113.03 | v102.23,114.3 98.42,114.3 v88.27,124.46
  Bottom 0.203: v134.62,92.71 140.34,92.71 141.6,93.98 141.6,105.41 149.22,113.03 150.5,113.03 151.76,114.3 SIDE6.8 | v125.73,113.03 111.12,113.03 108.58,115.57 103.5,115.57 v102.23,114.3 | v88.27,124.46 88.27,126.36 87,127.64 A2.D1
N$94  (via drill 0.61)
  Top 0.203: v138.43,125.73 140.34,125.73 145.41,120.65 145.41,114.3 149.22,110.49 150.5,110.49 151.76,109.22 SIDE6.12 | v81.92,132.08 81.92,130.81 v86.36,126.36
  Bottom 0.203: v138.43,125.73 136.53,125.73 133.35,128.91 133.35,130.18 121.92,141.6 95.89,141.6 93.34,139.06 88.9,139.06 v81.92,132.08 | v86.36,126.36 86.36,125.09 88.27,123.19 89.53,124.46 A2.E1
N$95  (via drill 0.61)
  Top 0.203: v152.4,78.11 154.31,80.01 154.31,104.14 152.4,106.05 SIDE6.14 | v116.84,80.01 105.41,91.44 105.41,93.98 97.79,101.6 v97.79,107.95 | v87,118.11 87,121.28 A2.F1
  Bottom 0.203: v152.4,78.11 118.75,78.11 v116.84,80.01 | v97.79,107.95 87.63,118.11 v87,118.11
N$96  (via drill 0.61)
  Top 0.203: v88.27,121.92 89.53,120.65 89.53,119.38 A2.H1 | v88.9,134.62 96.52,142.24 121.28,142.24 131.44,132.08 131.44,120.65 136.53,115.57 140.34,115.57 v147.96,107.95
  Bottom 0.203: v88.27,121.92 88.27,121.28 87.63,120.65 79.38,120.65 78.74,121.28 78.74,122.56 83.82,127.64 83.82,129.54 v88.9,134.62 | v147.96,107.95 147.96,106.68 149.22,105.41 150.5,105.41 151.76,104.14 SIDE6.16
N$97  (1 unrouted)
N$98  (via drill 0.61)
  Top 0.203: v144.78,95.89 144.78,88.27 137.79,81.28 119.38,81.28 v116.84,83.82 | v85.72,97.79 85.72,101.6 84.45,102.87 84.45,104.14 89.53,109.22 89.53,111.76 A2.K1
  Bottom 0.203: v144.78,95.89 149.22,100.33 150.5,100.33 151.76,101.6 SIDE6.18 | v116.84,83.82 101.6,83.82 87.63,97.79 v85.72,97.79
N$99  (via drill 0.61)
  Top 0.203: v143.51,88.9 143.51,87.63 137.79,81.92 120.65,81.92 116.84,85.72 116.84,107.31 v117.47,107.95 | v88.9,104.78 v92.08,101.6
  Bottom 0.203: v143.51,88.9 147.32,92.71 150.5,92.71 151.76,93.98 SIDE6.24 | v117.47,107.95 114.94,110.49 109.86,110.49 100.97,101.6 v92.08,101.6 | v88.9,104.78 87,106.68 87,108.58 A2.L1
N$100  (via drill 0.61)
  Top 0.203: v141.6,83.82 145.41,80.01 150.5,80.01 151.13,80.64 151.13,87 152.4,88.27 SIDE6.28 | v121.92,87.63 v125.09,84.45 | v106.05,87.63 100.97,92.71 100.97,97.16 92.71,105.41 90.17,105.41 A2.M1
  Bottom 0.203: v141.6,83.82 125.73,83.82 v125.09,84.45 | v121.92,87.63 120.02,87.63 119.38,88.27 106.68,88.27 v106.05,87.63
N$101  (via drill 0.61)
  Top 0.203: v80.01,118.11 81.28,119.38 81.28,120.02 89.53,128.27 89.53,129.54 81.92,137.16 81.92,138.43 83.19,139.7 92.08,139.7 95.89,143.51 125.09,143.51 141.6,127 141.6,125.73 v147.96,119.38
  Bottom 0.203: v80.01,118.11 78.74,116.84 78.74,111.76 78.11,111.12 78.11,108.58 81.92,104.78 84.45,104.78 85.09,105.41 85.72,105.41 87,104.14 87,103.5 A2.N1 | v147.96,119.38 149.22,118.11 153.03,118.11 153.67,117.47 153.67,98.42 152.4,97.16 SIDE6.22
N$102  (via drill 0.61)
  Top 0.203: v135.89,87.63 135.89,107.95 v132.08,111.76 | v119.38,123.19 119.38,125.09 116.2,128.27 111.12,128.27 v109.86,129.54 | v93.34,113.67 93.34,111.76 87.63,106.05 87.63,104.14 89.53,102.23 89.53,100.33 A2.P1
  Bottom 0.203: v135.89,87.63 150.5,87.63 151.76,86.36 SIDE6.30 | v132.08,111.76 128.27,115.57 123.83,115.57 119.38,120.02 v119.38,123.19 | v109.86,129.54 103.5,129.54 100.33,126.36 95.25,126.36 88.27,119.38 88.27,118.11 92.71,113.67 v93.34,113.67
N$103  (via drill 0.61)
  Top 0.203: v149.86,76.83 153.67,80.64 153.67,89.53 152.4,90.81 SIDE6.26 | v115.57,80.01 104.14,91.44 v104.14,93.98 | v89.53,97.79 87.63,97.79 87,97.16 A2.R1
  Bottom 0.203: v149.86,76.83 118.75,76.83 v115.57,80.01 | v104.14,93.98 103.5,94.61 92.71,94.61 v89.53,97.79
N$104  (via drill 0.61)
  Top 0.203: v127,149.86 59.69,149.86 58.42,148.59 58.42,139.7 59.69,138.43 59.69,135.25 v57.15,132.72 | v62.87,118.11 70.48,110.49 70.48,109.86 v75.56,104.78 | v83.19,102.87 85.09,100.97 85.09,98.42 84.45,97.79 84.45,96.52 87,93.98 89.53,93.98 A2.S1
  Bottom 0.203: v127,149.86 154.94,121.92 154.94,87 152.4,84.45 SIDE6.32 | v57.15,132.72 56.52,132.08 56.52,128.91 62.87,122.56 v62.87,118.11 | v75.56,104.78 79.38,104.78 80.01,104.14 81.92,104.14 v83.19,102.87
N$105  (via drill 0.61)
  Top 0.203: v140.34,82.55 135.25,77.47 104.78,77.47 99.69,82.55 85.72,82.55 85.09,83.19 85.09,88.27 86.36,89.53 A2.T1
  Bottom 0.203: v140.34,82.55 150.5,82.55 151.76,81.28 SIDE6.34
N$106  (via drill 0.61)
  Top 0.203: v81.92,65.41 81.92,62.87 81.28,62.23 81.28,59.69 v81.92,59.05 | v80.01,34.92 78.74,33.66 78.74,31.11 81.92,27.94 81.92,24.13 78.74,20.95 v78.74,13.34 | v154.94,79.38 154.94,116.2 152.4,118.75 SIDE6.4
  Bottom 0.203: v81.92,65.41 81.92,87.63 82.55,88.27 84.45,88.27 85.09,87.63 89.53,87.63 A2.U1 | v81.92,59.05 81.92,50.8 75.56,44.45 75.56,41.27 80.01,36.83 v80.01,34.92 | v78.74,13.34 90.81,1.27 131.44,1.27 156.21,26.04 156.21,78.11 v154.94,79.38
N$107  (via drill 0.61)
  Top 0.203: v88.27,89.53 87,88.27 87,84.45 A2.V1 | v91.44,92.71 94.61,95.89 v94.61,99.06 | v80.01,105.41 v81.92,107.31 | v77.47,107.95 77.47,109.86 75.56,111.76 75.56,113.03 76.2,113.67 76.2,117.47 72.39,121.28 72.39,128.91 v74.3,130.81 | v73.03,137.16 78.11,142.24 v92.08,142.24
  Bottom 0.203: v91.44,92.71 v88.27,89.53 | v94.61,99.06 92.71,99.06 84.45,107.31 v81.92,107.31 | v77.47,107.95 v80.01,105.41 | v74.3,130.81 75.56,132.08 75.56,135.25 73.66,137.16 v73.03,137.16 | v92.08,142.24 95.25,142.24 95.89,142.88 126.36,142.88 141.6,127.64 146.05,127.64 151.76,121.92 SIDE6.2
N$108  (via drill 0.61)
  Top 0.203: SIDE6.33 149.86,81.92 149.86,83.19 SIDE6.31 149.86,84.45 149.86,85.72 SIDE6.29 149.86,87 149.86,88.27 SIDE6.27 149.86,89.53 149.86,90.81 SIDE6.25 149.86,92.08 149.86,93.34 SIDE6.23 149.86,94.61 149.86,95.89 SIDE6.21 149.86,97.16 149.86,98.42 SIDE6.19 149.86,99.69 149.86,100.97 SIDE6.17 149.86,102.23 149.86,103.5 SIDE6.15 149.86,104.78 149.86,106.05 SIDE6.13 149.86,107.31 149.86,108.58 SIDE6.11 | v95.25,92.08 94.61,91.44 88.9,91.44 81.92,98.42 81.92,102.87 83.19,104.14 83.82,104.14 85.09,105.41 85.09,106.68 81.92,109.86 81.92,120.02 90.17,128.27 90.17,130.81 A2.C1 | v97.79,90.17 97.79,90.81 98.42,91.44 v100.33,91.44 | v118.75,79.38 v107.31,90.81 | SIDE6.9 149.86,112.39 149.86,113.67 SIDE6.7 149.86,114.94 149.86,116.2 SIDE6.5 149.86,117.47 149.86,118.75 SIDE6.3 149.86,120.02 149.86,121.28 SIDE6.1
  Bottom 0.203: v95.25,92.08 95.25,91.44 96.52,90.17 v97.79,90.17 | v100.33,91.44 106.68,91.44 v107.31,90.81 | v118.75,79.38 147.32,79.38 149.22,81.28 SIDE6.33 | SIDE6.9 149.86,111.12 149.86,109.86 SIDE6.11
N$109  (via drill 0.61)
  Top 0.203: SIDE7.33 5.08,81.92 5.08,83.19 SIDE7.31 5.08,84.45 5.08,85.72 SIDE7.29 5.08,87 5.08,88.27 SIDE7.27 5.08,89.53 5.08,90.81 SIDE7.25 5.08,92.08 5.08,93.34 SIDE7.23 5.08,94.61 5.08,95.89 SIDE7.21 5.08,97.16 5.08,98.42 SIDE7.19 5.08,99.69 5.08,100.97 SIDE7.17 5.08,102.23 5.08,103.5 SIDE7.15 5.08,104.78 5.08,106.05 SIDE7.13 5.08,107.31 5.08,108.58 SIDE7.11 5.08,109.86 5.08,111.12 SIDE7.9 5.08,112.39 5.08,113.67 SIDE7.7 5.08,114.94 5.08,116.2 SIDE7.5 5.08,117.47 5.08,118.75 SIDE7.3 5.08,120.02 5.08,121.28 SIDE7.1 | v73.66,132.08 75.56,133.99 75.56,135.25 74.93,135.89 v71.75,135.89 | v10.16,125.73 v16.51,125.73
  Bottom 0.203: v73.66,132.08 71.12,132.08 A3.C2 | v71.75,135.89 68.58,135.89 65.41,139.06 61.59,139.06 59.05,141.6 43.18,141.6 36.83,135.25 29.84,135.25 26.67,132.08 26.67,129.54 22.86,125.73 v16.51,125.73 | v10.16,125.73 8.26,125.73 5.08,122.56 SIDE7.1
N$110  (via drill 0.61)
  Top 0.203: v66.67,142.88 71.12,138.43 A3.A2
  Bottom 0.203: v66.67,142.88 59.69,149.86 35.56,149.86 13.34,127.64 13.34,127 8.26,121.92 SIDE7.2
N$111  (via drill 0.61)
  Top 0.203: v59.69,148.59 69.22,139.06 69.22,137.16 v71.75,134.62
  Bottom 0.203: v59.69,148.59 34.92,148.59 13.97,127.64 13.97,127 12.7,125.73 12.7,125.09 7.62,120.02 SIDE7.4 | v71.75,134.62 67.94,134.62 A3.B2
N$112  (via drill 0.61)
  Top 0.203: v59.69,147.32 68.58,138.43 68.58,136.53 72.39,132.72 72.39,129.54 v70.48,127.64
  Bottom 0.203: v59.69,147.32 34.29,147.32 14.61,127.64 14.61,127 13.34,125.73 13.34,123.19 7.62,117.47 SIDE7.6 | v70.48,127.64 67.94,127.64 A3.D2
N$113
  Bottom 0.203: SIDE7.8 7.62,113.67 6.35,112.39 6.35,106.05 6.99,105.41 8.26,105.41 16.51,113.67 16.51,114.94 17.14,115.57 20.95,115.57 24.77,119.38 24.77,123.19 29.84,128.27 31.11,128.27 31.75,128.91 31.75,130.18 32.38,130.81 35.56,130.81 40.64,135.89 53.34,135.89 53.98,136.53 57.15,136.53 67.94,125.73 70.48,125.73 A3.E2
N$114  (via drill 0.61)
  Top 0.203: v59.69,146.05 67.94,137.79 67.94,136.53 69.22,135.25 69.22,123.83 67.94,122.56 A3.F2
  Bottom 0.203: v59.69,146.05 59.05,145.41 43.18,145.41 36.83,139.06 29.84,139.06 23.5,132.72 20.32,132.72 15.24,127.64 15.24,127 13.97,125.73 13.97,118.75 7.62,112.39 SIDE7.10
N$115  (via drill 0.61)
  Top 0.203: v57.15,134.62 52.7,139.06 21.59,139.06 6.35,123.83 6.35,111.12 7.62,109.86 SIDE7.12
  Bottom 0.203: v57.15,134.62 70.48,121.28 70.48,119.38 A3.H2
N$116  (via drill 0.61)
  Top 0.203: v59.69,144.78 66.04,138.43 66.04,117.47 67.31,116.2 A3.J2
  Bottom 0.203: v59.69,144.78 59.05,144.15 42.55,144.15 36.83,138.43 29.84,138.43 22.86,131.44 19.68,131.44 15.88,127.64 15.88,127 14.61,125.73 14.61,114.3 7.62,107.31 SIDE7.14
N$117
  Bottom 0.203: SIDE7.16 8.26,104.14 17.14,113.03 24.77,113.03 27.3,115.57 49.53,115.57 50.8,116.84 51.44,116.84 60.33,107.95 68.58,107.95 70.48,109.86 70.48,111.76 A3.K2
N$118  (via drill 0.61)
  Top 0.203: v6.35,85.09 6.35,99.69 7.62,100.97 SIDE7.18 | v71.75,102.87 67.94,106.68 67.94,108.58 A3.L2
  Bottom 0.203: v6.35,85.09 16.51,85.09 20.32,81.28 67.31,81.28 75.56,89.53 75.56,99.06 v71.75,102.87
N$119  (via drill 0.61)
  Top 0.203: v3.81,100.33 3.81,122.56 20.95,139.7 53.98,139.7 v55.88,137.79 | v53.34,137.16 v53.34,134.62 | v73.66,118.75 75.56,116.84 75.56,113.67 v71.75,109.86
  Bottom 0.203: v3.81,100.33 5.71,100.33 6.99,99.06 SIDE7.20 | v55.88,137.79 53.98,137.79 v53.34,137.16 | v53.34,134.62 53.34,135.25 53.98,135.89 57.15,135.89 63.5,129.54 63.5,128.91 v73.66,118.75 | v71.75,109.86 71.75,107.31 71.12,106.68 A3.M2
N$120  (via drill 0.61)
  Top 0.203: v26.04,97.79 v29.21,97.79 | v40.64,94.61 51.44,94.61 v52.07,95.25
  Bottom 0.203: v26.04,97.79 17.14,97.79 15.88,96.52 8.26,96.52 SIDE7.22 | v29.21,97.79 37.47,97.79 v40.64,94.61 | v52.07,95.25 56.52,95.25 57.15,95.89 58.42,95.89 59.69,94.61 61.59,94.61 62.87,95.89 62.87,100.33 64.77,102.23 67.31,102.23 A3.N2
N$121  (via drill 0.61)
  Top 0.203: v25.4,131.44 14.61,131.44 8.89,125.73 8.89,95.89 7.62,94.61 SIDE7.24 | v66.04,109.86 66.04,107.31 70.48,102.87 70.48,100.33 A3.P2
  Bottom 0.203: v25.4,131.44 30.48,136.53 37.47,136.53 43.18,142.24 59.69,142.24 62.23,139.7 71.75,139.7 78.74,132.72 78.74,129.54 76.2,127 76.2,126.36 75.56,125.73 75.56,119.38 v66.04,109.86
N$122  (via drill 0.61)
  Top 0.203: v52.07,89.53 v53.34,88.27
  Bottom 0.203: v52.07,89.53 50.8,88.27 42.55,88.27 41.27,89.53 30.48,89.53 24.77,95.25 17.14,95.25 13.34,91.44 8.26,91.44 SIDE7.26 | v53.34,88.27 55.88,88.27 58.42,90.81 59.69,90.81 60.33,91.44 65.41,91.44 66.04,90.81 67.31,92.08 67.31,95.89 A3.R2
N$123  (via drill 0.61)
  Top 0.203: v34.92,83.82 36.2,85.09 36.2,86.36 31.75,90.81 31.75,94.61 32.38,95.25 36.2,95.25 48.26,83.19 52.07,83.19 53.98,85.09 59.05,85.09 61.59,87.63 62.87,87.63 67.94,92.71 70.48,92.71 A3.S2
  Bottom 0.203: v34.92,83.82 18.41,83.82 13.34,88.9 8.26,88.9 SIDE7.28
N$124  (via drill 0.61)
  Top 0.203: v53.34,93.98 57.78,89.53 v59.69,89.53
  Bottom 0.203: v53.34,93.98 43.81,93.98 34.92,102.87 29.84,102.87 27.3,100.33 17.14,100.33 14.61,97.79 6.99,97.79 6.35,97.16 6.35,88.27 7.62,87 SIDE7.30 | v59.69,89.53 63.5,85.72 65.41,85.72 67.31,87.63 67.31,89.53 A3.T2
N$125
  Top 0.203: SIDE7.34 7.62,80.64 14.61,73.66 55.24,73.66 57.78,71.12 61.59,71.12 69.85,79.38 69.85,85.72 70.48,86.36 A3.U2
N$126
  Top 0.203: SIDE7.32 8.26,83.82 24.77,83.82 30.48,78.11 43.18,78.11 46.99,81.92 66.04,81.92 67.31,83.19 A3.V2
N$127
  Bottom 0.203: SIDE8.10 19.68,116.84 18.41,118.11 17.14,118.11 15.24,120.02 15.24,125.73 16.51,127 16.51,127.64 19.68,130.81 22.86,130.81 29.84,137.79 36.83,137.79 42.55,143.51 64.77,143.51 66.67,141.6 73.66,141.6 76.83,138.43 A3.A1
N$128
  Bottom 0.203: SIDE8.6 20.32,122.56 27.3,129.54 27.3,132.08 29.84,134.62 36.83,134.62 43.18,140.97 59.05,140.97 66.67,133.35 73.03,133.35 73.66,133.99 A3.B1
N$129
  Bottom 0.203: SIDE8.8 20.32,120.02 29.21,128.91 29.21,132.72 29.84,133.35 36.83,133.35 43.18,139.7 59.05,139.7 69.85,128.91 73.66,128.91 A3.D1
N$130  (via drill 0.61)
  Top 0.203: v14.61,130.18 19.05,130.18 21.59,127.64 21.59,116.2 20.32,114.94 SIDE8.12 | v78.74,136.53 78.74,127 77.47,125.73 A3.E1
  Bottom 0.203: v14.61,130.18 34.92,150.5 66.67,150.5 78.74,138.43 v78.74,136.53
N$131  (via drill 0.61)
  Top 0.203: v27.3,128.27 27.3,119.38 20.32,112.39 SIDE8.14
  Bottom 0.203: v27.3,128.27 27.3,128.91 27.94,129.54 27.94,132.08 29.84,133.99 36.83,133.99 43.18,140.34 59.05,140.34 69.85,129.54 74.93,129.54 75.56,128.91 75.56,126.36 74.3,125.09 74.3,122.56 A3.F1
N$132
  Bottom 0.203: SIDE8.16 19.68,109.22 18.41,107.95 13.34,107.95 8.26,102.87 4.45,102.87 3.81,103.5 3.81,122.56 32.38,151.13 66.67,151.13 80.01,137.79 80.01,136.53 78.74,135.25 78.74,133.35 79.38,132.72 79.38,129.54 78.74,128.91 78.74,123.19 77.47,121.92 77.47,119.38 A3.H1
N$133  (via drill 0.61)
  Top 0.203: v44.45,102.87 44.45,112.39 45.09,113.03 v56.52,113.03 | v69.22,114.3 73.03,114.3 73.66,114.94 A3.J1
  Bottom 0.203: v44.45,102.87 42.55,102.87 40.01,105.41 29.84,105.41 28.57,104.14 20.95,104.14 SIDE8.20 | v56.52,113.03 57.78,114.3 v69.22,114.3
N$134  (via drill 0.61)
  Top 0.203: v34.29,107.95 34.29,106.05 v39.37,100.97 | v59.69,95.89 60.33,95.25 64.14,95.25 v67.31,98.42
  Bottom 0.203: v34.29,107.95 29.84,107.95 28.57,106.68 20.95,106.68 SIDE8.18 | v39.37,100.97 42.55,97.79 57.78,97.79 v59.69,95.89 | v67.31,98.42 67.31,99.69 76.83,109.22 76.83,111.76 A3.K1
N$135  (via drill 0.61)
  Top 0.203: v31.11,87.63 20.32,98.42 SIDE8.24 | v57.15,88.27 62.23,88.27 v66.04,92.08
  Bottom 0.203: v31.11,87.63 41.91,87.63 42.55,87 55.88,87 v57.15,88.27 | v66.04,92.08 66.04,99.06 73.66,106.68 73.66,108.58 A3.L1
N$136  (via drill 0.61)
  Top 0.203: v64.14,96.52 67.31,99.69 67.94,99.69 69.85,97.79 71.75,97.79 76.83,102.87 76.83,105.41 A3.M1
  Bottom 0.203: v64.14,96.52 59.05,91.44 53.98,91.44 53.34,90.81 53.34,89.53 51.44,87.63 42.55,87.63 41.27,88.9 30.48,88.9 25.4,93.98 20.95,93.98 SIDE8.28
N$137  (via drill 0.61)
  Top 0.203: v41.27,113.03 41.27,96.52 42.55,95.25 43.81,95.25 44.45,95.89 44.45,99.69 45.09,100.33 55.24,100.33 57.15,98.42 59.69,98.42 66.04,104.78 67.94,104.78 69.22,103.5 69.22,99.06 69.85,98.42 71.75,98.42 73.66,100.33 73.66,102.23 A3.N1
  Bottom 0.203: v41.27,113.03 29.84,113.03 24.77,107.95 19.68,107.95 19.05,107.31 19.05,103.5 20.32,102.23 SIDE8.22
N$138  (via drill 0.61)
  Top 0.203: v29.84,82.55 20.95,91.44 SIDE8.30 | v64.14,83.82 76.83,96.52 76.83,99.06 A3.P1
  Bottom 0.203: v29.84,82.55 36.83,82.55 37.47,81.92 62.23,81.92 v64.14,83.82
N$139  (via drill 0.61)
  Top 0.203: v57.15,94.61 72.39,94.61 73.66,95.89 A3.R1
  Bottom 0.203: v57.15,94.61 55.24,92.71 44.45,92.71 36.83,100.33 29.84,100.33 26.04,96.52 20.95,96.52 SIDE8.26
N$140  (via drill 0.61)
  Top 0.203: v30.48,79.38 20.95,88.9 SIDE8.32 | v62.87,64.14 v62.87,60.96 | v75.56,78.11 75.56,91.44 76.83,92.71 A3.S1
  Bottom 0.203: v30.48,79.38 36.2,79.38 49.53,66.04 55.88,66.04 58.42,63.5 62.23,63.5 v62.87,64.14 | v62.87,60.96 66.67,57.15 74.93,57.15 75.56,57.78 75.56,63.5 76.2,64.14 76.2,66.67 75.56,67.31 v75.56,78.11
N$141  (via drill 0.61)
  Top 0.203: v48.26,84.45 52.7,84.45 53.98,85.72 59.05,85.72 59.69,86.36 v59.69,87
  Bottom 0.203: v48.26,84.45 46.35,86.36 20.95,86.36 SIDE8.34 | v59.69,87 61.59,87 63.5,85.09 66.67,85.09 71.12,89.53 73.66,89.53 A3.T1
N$142  (via drill 0.61)
  Top 0.203: v38.1,79.38 24.77,92.71 19.68,92.71 19.05,93.34 19.05,122.56 20.32,123.83 SIDE8.4 | v45.09,72.39 55.88,72.39 57.78,70.48 61.59,70.48 71.12,80.01 v71.12,81.28
  Bottom 0.203: v38.1,79.38 v45.09,72.39 | v71.12,81.28 73.66,81.28 76.83,84.45 76.83,86.36 A3.U1
N$143  (via drill 0.61)
  Top 0.203: v74.3,104.78 71.75,107.31 v69.22,107.31 | v50.8,115.57 42.55,115.57 40.64,117.47 v40.64,118.11 | v26.04,121.92 26.04,123.83 v22.86,127
  Bottom 0.203: v74.3,104.78 78.74,100.33 78.74,92.08 74.3,87.63 74.3,84.45 A3.V1 | v69.22,107.31 59.05,107.31 v50.8,115.57 | v40.64,118.11 29.84,118.11 v26.04,121.92 | v22.86,127 20.95,127 SIDE8.2
N$144  (via drill 0.61)
  Top 0.203: SIDE8.33 17.78,87 17.78,88.27 SIDE8.31 17.78,89.53 17.78,90.81 SIDE8.29 17.78,92.08 17.78,93.34 SIDE8.27 17.78,94.61 17.78,95.89 SIDE8.25 17.78,97.16 17.78,98.42 SIDE8.23 17.78,99.69 17.78,100.97 SIDE8.21 17.78,102.23 17.78,103.5 SIDE8.19 17.78,104.78 17.78,106.05 SIDE8.17 17.78,107.31 17.78,108.58 SIDE8.15 17.78,109.86 17.78,111.12 SIDE8.13 17.78,112.39 17.78,113.67 SIDE8.11 17.78,114.94 17.78,116.2 SIDE8.9 17.78,117.47 17.78,118.75 SIDE8.7 17.78,120.02 17.78,121.28 SIDE8.5 17.78,122.56 17.78,123.83 SIDE8.3 17.78,125.09 17.78,126.36 SIDE8.1 | v76.83,135.89 76.83,132.08 A3.C1
  Bottom 0.203: v76.83,135.89 71.75,140.97 61.59,140.97 59.69,142.88 42.55,142.88 36.83,137.16 29.84,137.16 20.95,128.27 19.68,128.27 18.41,127 SIDE8.1
N$145  (via drill 0.61)
  Top 0.203: SIDE9.33 30.48,92.08 30.48,93.34 SIDE9.31 30.48,94.61 30.48,95.89 SIDE9.29 30.48,97.16 30.48,98.42 SIDE9.27 30.48,99.69 30.48,100.97 SIDE9.25 30.48,102.23 30.48,103.5 SIDE9.23 30.48,104.78 30.48,106.05 SIDE9.21 30.48,107.31 30.48,108.58 SIDE9.19 30.48,109.86 30.48,111.12 SIDE9.17 30.48,112.39 30.48,113.67 SIDE9.15 | 30.48,130.81 30.48,130.18 SIDE9.3 30.48,128.91 30.48,127.64 SIDE9.5 30.48,126.36 30.48,125.09 SIDE9.7 30.48,123.83 30.48,122.56 SIDE9.9 30.48,121.28 30.48,120.02 SIDE9.11 30.48,118.75 30.48,117.47 SIDE9.13 29.84,116.84 v27.3,114.3 | 30.48,130.81 30.48,131.44 SIDE9.1 | v49.53,131.44 57.78,131.44 A4.C2 | v38.1,129.54 36.83,129.54 35.56,130.81 30.48,130.81
  Bottom 0.203: v49.53,131.44 46.99,131.44 46.35,130.81 39.37,130.81 v38.1,129.54 | v27.3,114.3 29.84,114.3 SIDE9.15
N$146
  Bottom 0.203: SIDE9.2 33.66,132.08 36.2,132.08 42.55,138.43 55.24,138.43 55.88,139.06 57.15,139.06 57.78,138.43 A4.A2
N$147
  Bottom 0.203: SIDE9.4 33.66,129.54 35.56,127.64 41.91,127.64 42.55,128.27 48.9,128.27 54.61,133.99 A4.B2
N$148
  Bottom 0.203: SIDE9.6 33.66,127 41.27,127 42.55,125.73 52.7,125.73 54.61,127.64 A4.D2
N$149
  Bottom 0.203: SIDE9.8 33.66,124.46 41.27,124.46 42.55,123.19 56.52,123.19 57.78,124.46 A4.E2
N$150  (via drill 0.61)
  Top 0.203: v36.2,128.91 36.2,125.73 33.02,122.56 SIDE9.10 | v44.45,133.35 44.45,121.28 45.09,120.65 53.98,120.65 54.61,121.28 A4.F2
  Bottom 0.203: v36.2,128.91 40.64,133.35 v44.45,133.35
N$151  (via drill 0.61)
  Top 0.203: v41.27,120.65 43.81,120.65 44.45,120.02 44.45,118.75 45.09,118.11 57.78,118.11 A4.H2
  Bottom 0.203: v41.27,120.65 34.92,120.65 33.66,119.38 SIDE9.12
N$152
  Bottom 0.203: SIDE9.14 33.66,116.84 41.27,116.84 42.55,118.11 52.7,118.11 54.61,116.2 A4.J2
N$153  (via drill 0.61)
  Top 0.203: v37.47,110.49 33.66,114.3 SIDE9.16 | v50.16,110.49 53.34,110.49 54.61,111.76 57.78,111.76 A4.K2
  Bottom 0.203: v37.47,110.49 v50.16,110.49
N$154
  Bottom 0.203: SIDE9.18 33.66,111.76 41.27,111.76 42.55,113.03 51.44,113.03 54.61,109.86 A4.L2
N$155  (via drill 0.61)
  Top 0.203: v52.7,107.95 56.52,107.95 57.78,106.68 A4.M2
  Bottom 0.203: v52.7,107.95 42.55,107.95 41.27,109.22 33.66,109.22 SIDE9.20
N$156
  Bottom 0.203: SIDE9.22 33.66,106.68 41.27,106.68 42.55,105.41 52.7,105.41 54.61,103.5 A4.N2
N$157
  Bottom 0.203: SIDE9.24 33.66,104.14 38.73,104.14 42.55,100.33 57.78,100.33 A4.P2
N$158  (via drill 0.61)
  Top 0.203: v48.26,85.72 46.99,85.72 38.1,94.61 38.1,95.89 33.02,100.97 SIDE9.26 | v59.69,83.82 59.69,84.45 60.96,85.72 65.41,85.72 66.04,86.36 v66.04,87.63 | v62.87,90.17 62.87,90.81 61.59,92.08 57.15,92.08 55.24,93.98 55.24,95.89 A4.R2
  Bottom 0.203: v48.26,85.72 49.53,84.45 53.34,84.45 53.98,85.09 58.42,85.09 v59.69,83.82 | v66.04,87.63 63.5,90.17 v62.87,90.17
N$159
  Bottom 0.203: SIDE9.28 33.66,99.06 37.47,99.06 44.45,92.08 57.15,92.08 57.78,92.71 A4.S2
N$160  (via drill 0.61)
  Top 0.203: v45.72,90.81 54.61,90.81 A4.T2
  Bottom 0.203: v45.72,90.81 41.27,90.81 35.56,96.52 33.66,96.52 SIDE9.30
N$161  (via drill 0.61)
  Top 0.203: v50.8,89.53 53.34,87 57.78,87 A4.U2
  Bottom 0.203: v50.8,89.53 41.91,89.53 40.01,91.44 33.66,91.44 SIDE9.34
N$162
  Top 0.203: A4.V2 54.61,83.19 52.7,83.19 52.07,82.55 45.09,82.55 33.66,93.98 SIDE9.32
N$163
  Top 0.203: SIDE10.10 46.35,127 62.23,127 62.87,127.64 62.87,135.89 64.14,137.16 A4.A1
N$164
  Top 0.203: SIDE10.6 46.35,132.08 47.62,132.08 49.53,130.18 59.05,130.18 60.96,132.08 60.96,133.99 A4.B1
N$165
  Top 0.203: SIDE10.8 46.35,129.54 60.33,129.54 60.96,128.91 A4.D1
N$166
  Top 0.203: SIDE10.12 46.35,124.46 56.52,124.46 57.15,123.83 63.5,123.83 64.14,124.46 A4.E1
N$167
  Top 0.203: SIDE10.14 46.35,121.92 52.7,121.92 53.98,123.19 60.33,123.19 60.96,122.56 A4.F1
N$168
